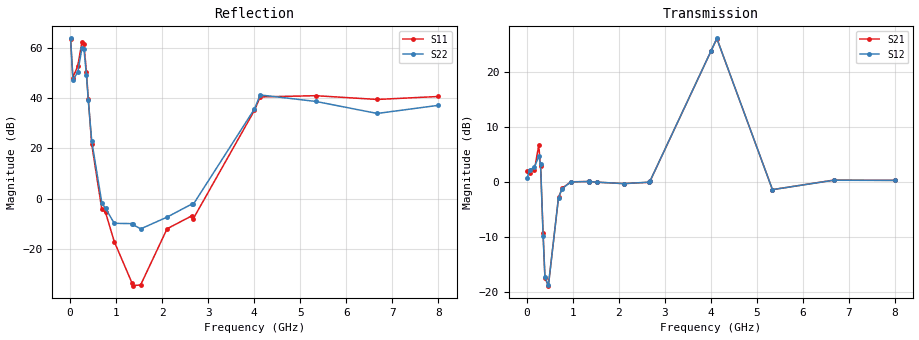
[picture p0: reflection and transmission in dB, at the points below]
!Agilent Technologies,N5230A,US43500312,A.07.50.67
!Agilent N5230A: A.07.50.67
!Date: Tuesday, June 09, 2015 15:38:32
!Correction: S11(Full 2 Port(1,2))
!S21(Full 2 Port(1,2))
!S12(Full 2 Port(1,2))
!S22(Full 2 Port(1,2))
!S2P File: Measurements: S11, S21, S12, S22:
# Hz S  MA  R 50
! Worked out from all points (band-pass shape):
!   1601 points, 10 MHz to 8 GHz, reference 50 ohm
!   highest |S21| = 26.10 dB at 4.13 GHz (marker M1); lowest = -18.8 dB at 469.4 MHz (marker M2)
!   |S21| within 3 dB of the highest: 3.985 GHz to 4.249 GHz (264.1 MHz wide, 6.41 % of centre)
!   lowest |S11| = -34.6 dB at 1.358 GHz (marker M3), VSWR 1.04, Z = 50.3 - j1.84 ohm
!   |S11| at or under -10 dB: 882.9 MHz to 2.155 GHz (1.272 GHz wide, 83.8 % of centre); 2.711 GHz to 2.896 GHz (184.4 MHz wide, 6.58 % of centre); 3.53 GHz to 3.548 GHz (18.35 MHz wide, 0.518 % of centre)
!   |S22| runs from -13.3 to 63.6 dB; largest |S21 - S12| = 0.51
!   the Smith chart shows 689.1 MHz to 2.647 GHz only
!   S11 on the Smith chart (normalised r, x): 689.1 MHz: 0.24, +0.06; 769 MHz: 0.37, -0.45; 958.8 MHz: 1.18, -0.25; 1.533 GHz: 0.96, +0.01; 2.107 GHz: 0.95, -0.51; 2.647 GHz: 0.55, -0.61
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1e7  1491 171.1  1.258 -20.4  1.089 -44.1  1520 -19.5
5.99375e7  253.8 328.7  1.222 -3.1  1.293 -6.5  228.3 93.0
1.648062e8  426 409.0  1.287 11.2  1.368 10.6  320.7 129.5
2.596875e8  1312 409.8  2.161 7.5  1.715 14.9  998.1 123.9
2.996375e8  1191 422.9  1.405 37.2  1.463 32.6  941.3 140.2
3.545688e8  329 464.5  0.3454 77.0  0.3251 61.0  285 190.8
3.945188e8  95.21 466.0  0.1339 60.8  0.1377 48.7  90.41 203.3
4.69425e8  11.98 469.2  0.1145 60.5  0.115 60.3  13.92 238.6
6.8915e8  0.61 533.0  0.7254 133.4  0.722 133.7  0.8202 407.2
7.6905e8  0.5317 593.6  0.8826 106.8  0.8747 106.9  0.6404 484.6
9.588125e8  0.1401 673.0  1.007 95.7  1.004 95.6  0.3227 571.7
1.343331e9  0.02125 680.7  1.014 98.1  1.014 98.1  0.318 761.3
1.358312e9  0.01862 641.1  1.013 98.1  1.013 98.2  0.3072 768.1
1.533094e9  0.01932 522.3  0.9988 98.3  1 98.3  0.25 849.2
2.107375e9  0.2516 279.1  0.9698 91.7  0.9706 91.8  0.429 1090.5
2.6467e9  0.4552 254.5  0.996 102.6  0.9994 102.7  0.7812 1212.2
2.676662e9  0.3988 255.8  1.017 103.1  1.02 103.1  0.7705 1219.4
4.005e9  56.35 343.1  15.6 116.5  15.63 116.8  60.02 1529.2
4.129844e9  104.5 336.5  20.19 59.6  20.28 59.9  114.3 1505.8
5.338331e9  110.5 266.9  0.8551 16.1  0.8548 16.7  84.98 1411.5
6.671662e9  93.02 294.8  1.044 14.1  1.041 15.1  49.05 1352.1
8e9  106.5 315.9  1.038 10.2  1.037 9.9  71.09 1315.2
